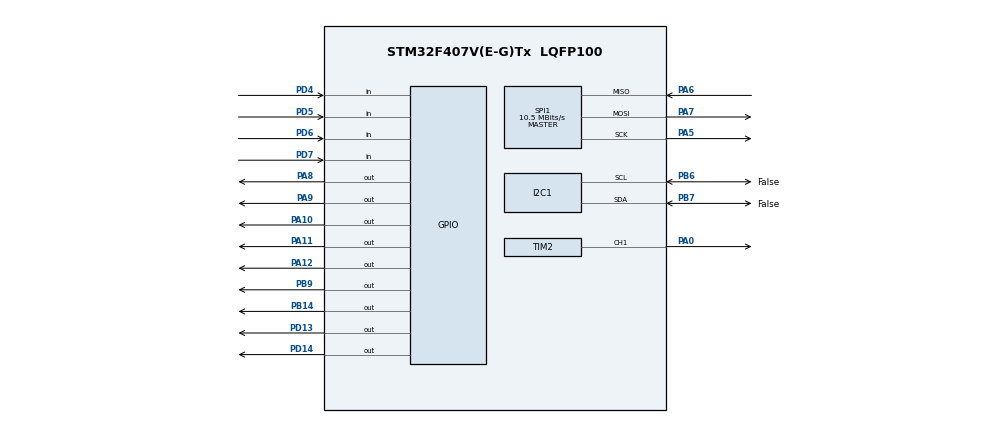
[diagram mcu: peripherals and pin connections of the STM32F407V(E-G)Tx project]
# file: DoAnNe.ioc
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Mcu.Family=STM32F4
Mcu.Name=STM32F407V(E-G)Tx
Mcu.Package=LQFP100
NVIC.PriorityGroup=NVIC_PRIORITYGROUP_4
PA0-WKUP.Signal=S_TIM2_CH1_ETR
PA10.GPIO_PuPd=GPIO_PULLDOWN
PA10.Signal=GPIO_Output
PA11.GPIO_PuPd=GPIO_PULLUP
PA11.Signal=GPIO_Output
PA12.GPIO_PuPd=GPIO_PULLUP
PA12.Signal=GPIO_Output
PA13.Mode=Serial_Wire
PA13.Signal=SYS_JTMS-SWDIO
PA14.Mode=Serial_Wire
PA14.Signal=SYS_JTCK-SWCLK
PA5.Mode=Full_Duplex_Master
PA5.Signal=SPI1_SCK
PA6.Mode=Full_Duplex_Master
PA6.Signal=SPI1_MISO
PA7.Mode=Full_Duplex_Master
PA7.Signal=SPI1_MOSI
PA8.Signal=GPIO_Output
PA9.GPIO_PuPd=GPIO_PULLUP
PA9.Signal=GPIO_Output
PB14.Signal=GPIO_Output
PB6.GPIO_Label=False
PB6.GPIO_Pu=GPIO_PULLUP
PB6.Mode=I2C
PB6.Signal=I2C1_SCL
PB7.GPIO_Label=False
PB7.GPIO_Pu=GPIO_PULLUP
PB7.Mode=I2C
PB7.Signal=I2C1_SDA
PB9.Signal=GPIO_Output
PD13.Signal=GPIO_Output
PD14.Signal=GPIO_Output
PD4.GPIO_PuPd=GPIO_PULLDOWN
PD4.Signal=GPIO_Input
PD5.GPIO_PuPd=GPIO_PULLDOWN
PD5.Signal=GPIO_Input
PD6.GPIO_PuPd=GPIO_PULLDOWN
PD6.Signal=GPIO_Input
PD7.GPIO_PuPd=GPIO_PULLDOWN
PD7.Signal=GPIO_Input
PH0-OSC_IN.Mode=HSE-External-Oscillator
PH0-OSC_IN.Signal=RCC_OSC_IN
PH1-OSC_OUT.Mode=HSE-External-Oscillator
PH1-OSC_OUT.Signal=RCC_OSC_OUT
ProjectManager.HeapSize=0x200
ProjectManager.StackSize=0x400
ProjectManager.TargetToolchain=STM32CubeIDE
RCC.48MHZClocksFreq_Value=42000000
RCC.AHBFreq_Value=84000000
RCC.APB1CLKDivider=RCC_HCLK_DIV2
RCC.APB1Freq_Value=42000000
RCC.APB1TimFreq_Value=84000000
RCC.APB2Freq_Value=84000000
RCC.APB2TimFreq_Value=84000000
RCC.CortexFreq_Value=84000000
RCC.HCLKFreq_Value=84000000
RCC.HSE_VALUE=25000000
RCC.HSI_VALUE=16000000
RCC.LSE_VALUE=32768
RCC.PLLM=8
RCC.PLLN=84
RCC.SYSCLKFreq_VALUE=84000000
RCC.SYSCLKSource=RCC_SYSCLKSOURCE_PLLCLK
RCC.VCOOutputFreq_Value=168000000
SH.S_TIM2_CH1_ETR.0=TIM2_CH1,PWM Generation1 CH1
SPI1.BaudRatePrescaler=SPI_BAUDRATEPRESCALER_8
SPI1.CalculateBaudRate=10.5 MBits/s
SPI1.Direction=SPI_DIRECTION_2LINES
SPI1.Mode=SPI_MODE_MASTER
SPI1.VirtualType=VM_MASTER
TIM2.Channel-PWM\ Generation1\ CH1=TIM_CHANNEL_1
TIM2.Prescaler=199
board=custom

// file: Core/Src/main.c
/* USER CODE BEGIN Header */
/**
  ******************************************************************************
  * @file           : main.c
  * @brief          : Main program body
  ******************************************************************************
  * @attention
  *
  * Copyright (c) 2025 STMicroelectronics.
  * All rights reserved.
  *
  * This software is licensed under terms that can be found in the LICENSE file
  * in the root directory of this software component.
  * If no LICENSE file comes with this software, it is provided AS-IS.
  *
  ******************************************************************************
  */
/* USER CODE END Header */
#include "main.h"

/* USER CODE BEGIN Includes */
#include "RC522.h"
#include "string.h"
#include "keypad.h"
#include "i2c-lcd.h"

/* USER CODE END Includes */

/* USER CODE BEGIN PTD */
GPIO_TypeDef* ROW_PORT[4] = {R_PORT, R_PORT, R_PORT, R_PORT};
uint16_t ROW_PIN[4] = {R1_PIN, R2_PIN, R3_PIN, R4_PIN};

GPIO_TypeDef* COL_PORT[4] = {C_PORT, C_PORT, C_PORT, C_PORT};
uint16_t COL_PIN[4] = {C1_PIN, C2_PIN, C3_PIN, C4_PIN};
/* USER CODE END PTD */

I2C_HandleTypeDef hi2c1;

SPI_HandleTypeDef hspi1;

TIM_HandleTypeDef htim2;

/* USER CODE BEGIN PV */
uint8_t status;
uint8_t str[16];
uint8_t sNum[5];
// Định nghĩa số lượng thẻ được phép
#define NUM_ALLOWED_CARDS 20

// Danh sách các UID hợp lệ (Master Database)
const uint8_t Allowed_UIDs[NUM_ALLOWED_CARDS][5] = {
    {44, 245, 250, 3, 32},   // Thẻ 1
    {227, 26, 186, 27, 88},   // Thẻ 2
	{186, 233, 43, 26, 98},
    {52, 86, 74, 90, 114},
    {52,208 ,134 ,90 ,56 }
};

char *msg1 = "Reading from CARD\r\n";
char *msg2 = "Reading from TAG\r\n";
/* USER CODE END PV */

void SystemClock_Config(void);
static void MX_GPIO_Init(void);
static void MX_SPI1_Init(void);
static void MX_TIM2_Init(void);
static void MX_I2C1_Init(void);

/* USER CODE BEGIN 0 */

void Green_LED_On(uint16_t ms)
{
    HAL_GPIO_WritePin(GPIOA, GPIO_PIN_1, GPIO_PIN_SET);
    HAL_Delay(ms);
    HAL_GPIO_WritePin(GPIOA, GPIO_PIN_1, GPIO_PIN_RESET);
}

void Set_Servo_Angle(TIM_HandleTypeDef *htim, uint32_t channel, uint8_t angle)
{
    uint32_t pulse = 210 + angle * (1050 - 210) / 180;
    __HAL_TIM_SET_COMPARE(htim, channel, pulse);
}
void Auto_Open_Door(TIM_HandleTypeDef *htim, uint32_t channel)
{
					for(uint8_t angle=0; angle<=90; angle+=5)
		  		  {
		  			  Set_Servo_Angle(&htim2, TIM_CHANNEL_1, angle);
		  			  HAL_Delay(10);
		  		  }
					Buzzer_Beep_Short();
					Green_LED_On(2000);
		  		  HAL_Delay(2000);
		  		  for(uint8_t angle=90; angle>0; angle-=5)
		  		  {
		  			  Set_Servo_Angle(&htim2, TIM_CHANNEL_1, angle);
		  			  HAL_Delay(10);
		  		  }
}
uint8_t Check_Card_Access(uint8_t *inputUID) {
    uint8_t i, j;
    uint8_t match_count;

    // Duyệt qua từng thẻ trong danh sách cho phép
    for (i = 0; i < NUM_ALLOWED_CARDS; i++) {
        match_count = 0;

        // So sánh từng byte của thẻ (5 bytes)
        for (j = 0; j < 5; j++) {
            if (inputUID[j] == Allowed_UIDs[i][j]) {
                match_count++;
            } else {
                break; // Nếu lệch 1 byte thì bỏ qua thẻ này ngay
            }
        }

        // Nếu khớp đủ 5 byte -> Thẻ hợp lệ
        if (match_count == 5) {
            return 1; // Hợp lệ (True)
        }
    }

    return 0; // Không tìm thấy thẻ nào khớp (False)
}
void Buzzer_Beep_Short()
{
    HAL_GPIO_WritePin(GPIOD, GPIO_PIN_14, GPIO_PIN_SET);
    HAL_Delay(100);
    HAL_GPIO_WritePin(GPIOD, GPIO_PIN_14, GPIO_PIN_RESET);
}

void Buzzer_Beep_Long()
{
    HAL_GPIO_WritePin(GPIOD, GPIO_PIN_14, GPIO_PIN_SET);
    HAL_Delay(500);
    HAL_GPIO_WritePin(GPIOD, GPIO_PIN_14, GPIO_PIN_RESET);
}

/* USER CODE END 0 */

int main(void)
{

  /* MCU Configuration--------------------------------------------------------*/

  /* Reset of all peripherals, Initializes the Flash interface and the Systick. */
  HAL_Init();

  /* Configure the system clock */
  SystemClock_Config();

  /* Initialize all configured peripherals */
  MX_GPIO_Init();
  MX_SPI1_Init();
  MX_TIM2_Init();
  MX_I2C1_Init();
  /* USER CODE BEGIN 2 */
  MFRC522_Init();
  HAL_TIM_PWM_Start(&htim2, TIM_CHANNEL_1);
  lcd_init();
  lcd_clear();
  lcd_put_cur(0, 3);
  lcd_send_string("Welcome !");
  HAL_Delay(2000);

  lcd_clear();
  lcd_put_cur(0, 0);
  lcd_send_string("Scan to open");
  lcd_put_cur(1, 0);
  lcd_send_string("Press A: In Pass");

  /* USER CODE END 2 */

  /* Infinite loop */
  /* USER CODE BEGIN WHILE */
  uint8_t mode = 0;  // 0=RFID, 1=Password
        char key;
        char correctPass[5] = "1234";
        char inputPass[5] = "";
        uint8_t passIndex = 0;

  while (1)
  {
    /* USER CODE END WHILE */

    /* USER CODE BEGIN 3 */

	            /* ====== QUÉT PHÍM KEYPAD ====== */
	            key = Keypad_GetKey();
	            if (key != 0)
	            {
	                HAL_Delay(120);

	                if (mode == 0)
	                {
	                    if (key == 'A')
	                    {
	                        mode = 1;
	                        passIndex = 0;
	                        inputPass[0] = '\0';

	                        lcd_clear();
	                        lcd_put_cur(0, 0);
	                        lcd_send_string("Enter Pass");
	                        lcd_put_cur(1, 0);
	                    }
	                }

	                else if (mode == 1)
	                {
	                    if (key >= '0' && key <= '9')
	                    {
	                    	inputPass[passIndex++] = key;
	                    	inputPass[passIndex] = '\0';

	                    	lcd_put_cur(1, passIndex-1);
	                    	lcd_send_data('*');

	                    	//lcd_send_data(key);
	                    }
	                    // ❗ BACKSPACE
	                     else if (key == 'D')
	                       {
	                           if (passIndex > 0)
	                           {
	                               passIndex--;
	                               inputPass[passIndex] = '\0';

	                               lcd_put_cur(1, passIndex);
	                               lcd_send_data(' ');
	                               lcd_put_cur(1, passIndex);
	                           }
	                       }
	                     else if (key == '#')
	                         {
	                    	 	 if (passIndex == 4)
	                    	 	 	 {
	                    	 		 	 if (strcmp(inputPass, correctPass) == 0)
	                    	 	{
	                        	    lcd_clear();
	                        	    lcd_put_cur(0, 0);
	                        	    lcd_send_string("Correct Pass");
	                        	    Auto_Open_Door(&htim2, TIM_CHANNEL_1);
	                        	}

	                        	else
	                        	{
	                        	    lcd_clear();
	                        	    lcd_put_cur(0, 0);
	                        	    lcd_send_string("Wrong Pass");

	                        	    for (int i = 0; i < 3; i++)
	                        	    {
	                        	        Buzzer_Beep_Long();
	                        	        HAL_Delay(150);
	                        	    }
	                        	}

	                        	mode = 0;
	                        	passIndex = 0;
	                        	inputPass[0] = '\0';

	                        	lcd_clear();
	                        	lcd_put_cur(0, 0);
	                        	lcd_send_string("Scan to open");
	                        	lcd_put_cur(1, 0);
	                        	lcd_send_string("Press A: In Pass");

	                        }
	                    	 	else
	                    	 	        {
	                    	 	            lcd_put_cur(0, 0);
	                    	 	            lcd_send_string("Need 4 digits ");
	                    	 	        }

	                    }
	                }
	            }

	            /* ====== QUÉT THẺ RFID ====== */
	            if (mode == 0)
	            {
	                status = MFRC522_Request(PICC_REQIDL, str);
	                status = MFRC522_Anticoll(str);

	                if (status == MI_OK)
	                {
	                    memcpy(sNum, str, 5);

	                    if (Check_Card_Access(str))
	                    {
	                        lcd_clear();
	                        lcd_put_cur(0, 0);
	                        lcd_send_string("Access Granted");

	                        Auto_Open_Door(&htim2, TIM_CHANNEL_1);

	                        lcd_clear();
	                        lcd_put_cur(0, 0);
	                        lcd_send_string("Scan to open");
	                        lcd_put_cur(1, 0);
	                        lcd_send_string("Press A: In Pass");
	                    }

	                    else
	                    {
	                        lcd_clear();
	                        lcd_put_cur(0, 0);
	                        lcd_send_string("Access Denied");
	                        lcd_put_cur(1, 0);
	                        lcd_send_string("Try Again");

	                        Buzzer_Beep_Long();
	                        HAL_Delay(500);
	                        Buzzer_Beep_Long();

	                        lcd_clear();
	                        lcd_put_cur(0, 0);
	                        lcd_send_string("Scan to open");
	                        lcd_put_cur(1, 0);
	                        lcd_send_string("Press A: In Pass");
	                    }

	                }
	            }

  }
  /* USER CODE END 3 */
}

void SystemClock_Config(void)
{
  RCC_OscInitTypeDef RCC_OscInitStruct = {0};
  RCC_ClkInitTypeDef RCC_ClkInitStruct = {0};

  /** Configure the main internal regulator output voltage
  */
  __HAL_RCC_PWR_CLK_ENABLE();
  __HAL_PWR_VOLTAGESCALING_CONFIG(PWR_REGULATOR_VOLTAGE_SCALE1);

  /** Initializes the RCC Oscillators according to the specified parameters
  * in the RCC_OscInitTypeDef structure.
  */
  RCC_OscInitStruct.OscillatorType = RCC_OSCILLATORTYPE_HSI;
  RCC_OscInitStruct.HSIState = RCC_HSI_ON;
  RCC_OscInitStruct.HSICalibrationValue = RCC_HSICALIBRATION_DEFAULT;
  RCC_OscInitStruct.PLL.PLLState = RCC_PLL_ON;
  RCC_OscInitStruct.PLL.PLLSource = RCC_PLLSOURCE_HSI;
  RCC_OscInitStruct.PLL.PLLM = 8;
  RCC_OscInitStruct.PLL.PLLN = 168;
  RCC_OscInitStruct.PLL.PLLP = RCC_PLLP_DIV2;
  RCC_OscInitStruct.PLL.PLLQ = 4;
  if (HAL_RCC_OscConfig(&RCC_OscInitStruct) != HAL_OK)
  {
    Error_Handler();
  }

  /** Initializes the CPU, AHB and APB buses clocks
  */
  RCC_ClkInitStruct.ClockType = RCC_CLOCKTYPE_HCLK|RCC_CLOCKTYPE_SYSCLK
                              |RCC_CLOCKTYPE_PCLK1|RCC_CLOCKTYPE_PCLK2;
  RCC_ClkInitStruct.SYSCLKSource = RCC_SYSCLKSOURCE_PLLCLK;
  RCC_ClkInitStruct.AHBCLKDivider = RCC_SYSCLK_DIV2;
  RCC_ClkInitStruct.APB1CLKDivider = RCC_HCLK_DIV4;
  RCC_ClkInitStruct.APB2CLKDivider = RCC_HCLK_DIV2;

  if (HAL_RCC_ClockConfig(&RCC_ClkInitStruct, FLASH_LATENCY_2) != HAL_OK)
  {
    Error_Handler();
  }
}

static void MX_I2C1_Init(void)
{

  hi2c1.Instance = I2C1;
  hi2c1.Init.ClockSpeed = 100000;
  hi2c1.Init.DutyCycle = I2C_DUTYCYCLE_2;
  hi2c1.Init.OwnAddress1 = 0;
  hi2c1.Init.AddressingMode = I2C_ADDRESSINGMODE_7BIT;
  hi2c1.Init.DualAddressMode = I2C_DUALADDRESS_DISABLE;
  hi2c1.Init.OwnAddress2 = 0;
  hi2c1.Init.GeneralCallMode = I2C_GENERALCALL_DISABLE;
  hi2c1.Init.NoStretchMode = I2C_NOSTRETCH_DISABLE;
  if (HAL_I2C_Init(&hi2c1) != HAL_OK)
  {
    Error_Handler();
  }

}

static void MX_SPI1_Init(void)
{

  /* SPI1 parameter configuration*/
  hspi1.Instance = SPI1;
  hspi1.Init.Mode = SPI_MODE_MASTER;
  hspi1.Init.Direction = SPI_DIRECTION_2LINES;
  hspi1.Init.DataSize = SPI_DATASIZE_8BIT;
  hspi1.Init.CLKPolarity = SPI_POLARITY_LOW;
  hspi1.Init.CLKPhase = SPI_PHASE_1EDGE;
  hspi1.Init.NSS = SPI_NSS_SOFT;
  hspi1.Init.BaudRatePrescaler = SPI_BAUDRATEPRESCALER_8;
  hspi1.Init.FirstBit = SPI_FIRSTBIT_MSB;
  hspi1.Init.TIMode = SPI_TIMODE_DISABLE;
  hspi1.Init.CRCCalculation = SPI_CRCCALCULATION_DISABLE;
  hspi1.Init.CRCPolynomial = 10;
  if (HAL_SPI_Init(&hspi1) != HAL_OK)
  {
    Error_Handler();
  }

}

static void MX_TIM2_Init(void)
{

  TIM_ClockConfigTypeDef sClockSourceConfig = {0};
  TIM_MasterConfigTypeDef sMasterConfig = {0};
  TIM_OC_InitTypeDef sConfigOC = {0};

  htim2.Instance = TIM2;
  htim2.Init.Prescaler = 199;
  htim2.Init.CounterMode = TIM_COUNTERMODE_UP;
  htim2.Init.Period = 8400-1;
  htim2.Init.ClockDivision = TIM_CLOCKDIVISION_DIV1;
  htim2.Init.AutoReloadPreload = TIM_AUTORELOAD_PRELOAD_DISABLE;
  if (HAL_TIM_Base_Init(&htim2) != HAL_OK)
  {
    Error_Handler();
  }
  sClockSourceConfig.ClockSource = TIM_CLOCKSOURCE_INTERNAL;
  if (HAL_TIM_ConfigClockSource(&htim2, &sClockSourceConfig) != HAL_OK)
  {
    Error_Handler();
  }
  if (HAL_TIM_PWM_Init(&htim2) != HAL_OK)
  {
    Error_Handler();
  }
  sMasterConfig.MasterOutputTrigger = TIM_TRGO_RESET;
  sMasterConfig.MasterSlaveMode = TIM_MASTERSLAVEMODE_DISABLE;
  if (HAL_TIMEx_MasterConfigSynchronization(&htim2, &sMasterConfig) != HAL_OK)
  {
    Error_Handler();
  }
  sConfigOC.OCMode = TIM_OCMODE_PWM1;
  sConfigOC.Pulse = 0;
  sConfigOC.OCPolarity = TIM_OCPOLARITY_HIGH;
  sConfigOC.OCFastMode = TIM_OCFAST_DISABLE;
  if (HAL_TIM_PWM_ConfigChannel(&htim2, &sConfigOC, TIM_CHANNEL_1) != HAL_OK)
  {
    Error_Handler();
  }
  HAL_TIM_MspPostInit(&htim2);

}

static void MX_GPIO_Init(void)
{
  GPIO_InitTypeDef GPIO_InitStruct = {0};

  /* GPIO Ports Clock Enable */
  __HAL_RCC_GPIOH_CLK_ENABLE();
  __HAL_RCC_GPIOA_CLK_ENABLE();
  __HAL_RCC_GPIOB_CLK_ENABLE();
  __HAL_RCC_GPIOD_CLK_ENABLE();

  /*Configure GPIO pin Output Level */
  HAL_GPIO_WritePin(GPIOB, GPIO_PIN_14|GPIO_PIN_9, GPIO_PIN_RESET);

  /*Configure GPIO pin Output Level */
  HAL_GPIO_WritePin(GPIOA, GPIO_PIN_8, GPIO_PIN_RESET);

  /*Configure GPIO pin Output Level */
  HAL_GPIO_WritePin(GPIOD, GPIO_PIN_4|GPIO_PIN_5|GPIO_PIN_6|GPIO_PIN_7, GPIO_PIN_RESET);

  /*Configure GPIO pins : PB14 PB9 */
  GPIO_InitStruct.Pin = GPIO_PIN_14|GPIO_PIN_9;
  GPIO_InitStruct.Mode = GPIO_MODE_OUTPUT_PP;
  GPIO_InitStruct.Pull = GPIO_NOPULL;
  GPIO_InitStruct.Speed = GPIO_SPEED_FREQ_LOW;
  HAL_GPIO_Init(GPIOB, &GPIO_InitStruct);

  /*Configure GPIO pins : PA1 PA8 */
  GPIO_InitStruct.Pin = GPIO_PIN_1 | GPIO_PIN_8;

  GPIO_InitStruct.Mode = GPIO_MODE_OUTPUT_PP;
  GPIO_InitStruct.Pull = GPIO_NOPULL;
  GPIO_InitStruct.Speed = GPIO_SPEED_FREQ_LOW;
  HAL_GPIO_Init(GPIOA, &GPIO_InitStruct);

  /*Configure GPIO pins : PA9 PA10 PA11 PA12 */
  GPIO_InitStruct.Pin = GPIO_PIN_9|GPIO_PIN_10|GPIO_PIN_11|GPIO_PIN_12;
  GPIO_InitStruct.Mode = GPIO_MODE_INPUT;
  GPIO_InitStruct.Pull = GPIO_PULLUP;
  HAL_GPIO_Init(GPIOA, &GPIO_InitStruct);

  /*Configure GPIO pins : PD4 PD5 PD6 PD7 */
  GPIO_InitStruct.Pin = GPIO_PIN_4|GPIO_PIN_5|GPIO_PIN_6|GPIO_PIN_7;
  GPIO_InitStruct.Mode = GPIO_MODE_OUTPUT_PP;
  GPIO_InitStruct.Pull = GPIO_NOPULL;
  GPIO_InitStruct.Speed = GPIO_SPEED_FREQ_LOW;
  HAL_GPIO_Init(GPIOD, &GPIO_InitStruct);

  /* USER CODE BEGIN MX_GPIO_Init_2 */
  /* Cấu hình Buzzer tại PD14 */
  GPIO_InitStruct.Pin = GPIO_PIN_14;
  GPIO_InitStruct.Mode = GPIO_MODE_OUTPUT_PP;
  GPIO_InitStruct.Pull = GPIO_NOPULL;
  GPIO_InitStruct.Speed = GPIO_SPEED_FREQ_LOW;
  HAL_GPIO_Init(GPIOD, &GPIO_InitStruct);
  /* USER CODE END MX_GPIO_Init_2 */
}

void Error_Handler(void)
{
  __disable_irq();
  while (1)
  {
  }
}
